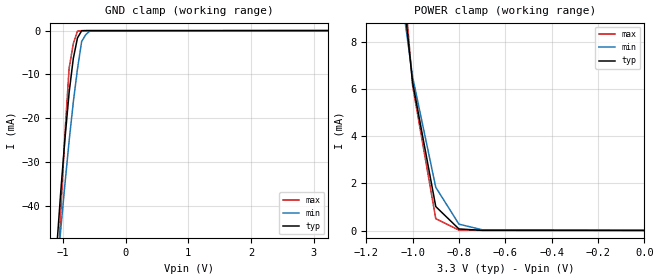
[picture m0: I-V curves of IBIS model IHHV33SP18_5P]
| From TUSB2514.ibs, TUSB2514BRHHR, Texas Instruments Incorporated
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|   Model Cell IHHV33SP18_5P
|IHHV33SP18_3P3
[Model]   IHHV33SP18_5P
Model_type   Input
Polarity   Non-Inverting
Vinl =  0.8V
Vinh =  2V
C_comp   0.3512646p   0.2812899p   0.4190439p
[Model Spec]
Vinl   0.8V   0.8V   0.8V
Vinh   2V   2V   2V
[Temperature Range]   25   125   -40
[Voltage Range]   3.3   3.135   3.465
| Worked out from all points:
|   GND clamp passes 1 mA (typ) near -0.74 V on its own axis
|   POWER clamp passes 1 mA (typ) near -0.90 V on its own axis
[POWER_clamp]
|   voltage   I(typ)   I(min)   I(max)
-3.3V     300.9mA    232.9mA    387.3mA
-1.033V   9.389mA    8.899mA    10.08mA
-1V       6.287mA    6.515mA    6.151mA
-900mV    1.015mA    1.832mA    501uA
-800mV    66.57uA    270.9uA    19.03uA
-700mV    7.097uA    32.42uA    7.55uA
-11.55fV  3.926uA    2.493uA    7.035uA
[GND_clamp]
|   voltage   I(typ)   I(min)   I(max)
-3.3V     -748.1mA   -693.8mA   -953mA
-1.1V     -50.29mA   -56.25mA   -62.5mA
-1.033V   -36.87mA   -45.48mA   -41.61mA
-966.7mV  -24.84mA   -35.16mA   -23.65mA
-900mV    -14.19mA   -25.28mA   -8.624mA
-833.3mV  -6.398mA   -16.4mA    -2.997mA
-766.7mV  -1.68mA    -8.805mA   -123.2uA
-700mV    -38.55uA   -2.483mA   -1.24uA
-633.3mV  -13.11uA   -898uA     -422.3nA
-566.7mV  -262.3nA   -71.22uA   -8.981nA
3.233V    3.908uA    2.507uA    6.929uA
